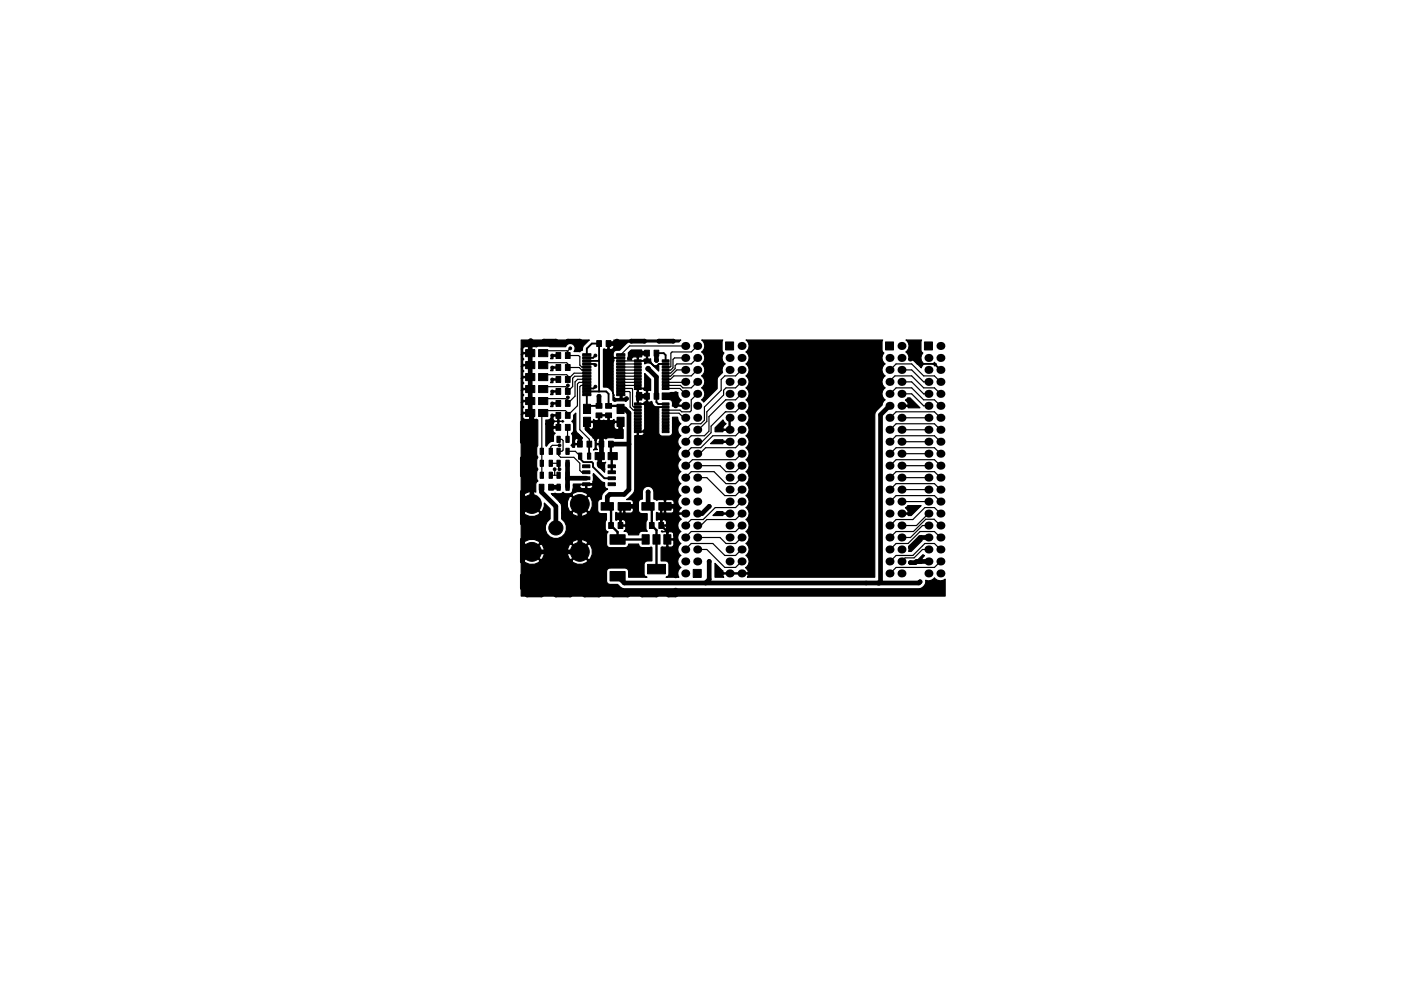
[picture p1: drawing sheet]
<svg xmlns="http://www.w3.org/2000/svg" width="297mm" height="210mm" viewBox="0 0 297 210" stroke-linecap="round" stroke-linejoin="round" font-family="sans-serif">
<g fill="#000" stroke="#000" stroke-width=".21">
<path d="M111.4 79.3h2v1.5h-2zM111.4 76.7h2v1.5h-2zM111.4 74.2h2v1.5h-2zM114.2 79.3h1.9v1.5h-1.9zM114.2 76.7h1.9v1.5h-1.9zM114.2 74.2h1.9v1.5h-1.9zM117.9 79.9h1v1.2h-1zM117.9 77.3h1v1.3h-1zM117.9 74.8h1v1.3h-1zM119.9 79.9h1v1.2h-1zM119.9 77.3h1v1.3h-1zM119.9 74.8h1v1.3h-1z"/>
<path d="M123.5 75h1.8v.5h-1.8zM123.5 75.7h1.8v.4h-1.8zM123.5 76.3h1.8v.5h-1.8zM123.5 77h1.8v.4h-1.8zM123.5 77.6h1.8v.5h-1.8zM123.5 78.3h1.8v.4h-1.8zM123.5 78.9h1.8v.5h-1.8zM123.5 79.6h1.8v.4h-1.8zM126.5 72.3h1v1.2h-1zM128.5 72.3h1v1.2h-1zM130.7 79.6h1.8v.4h-1.8zM130.7 78.9h1.8v.5h-1.8z"/>
<path d="M130.7 78.3h1.8v.4h-1.8zM130.7 77.6h1.8v.5h-1.8zM130.7 77h1.8v.4h-1.8zM130.7 76.3h1.8v.5h-1.8zM130.7 75.7h1.8v.4h-1.8zM130.7 75h1.8v.5h-1.8zM134.5 76.3h1.5v.5h-1.5zM134.5 77h1.5v.4h-1.5zM134.5 77.6h1.5v.5h-1.5zM134.5 78.3h1.5v.4h-1.5zM134.5 78.9h1.5v.5h-1.5zM136.7 74.3h1v1.2h-1z"/>
<path d="M138.7 74.3h1v1.2h-1zM140.4 78.9h1.5v.5h-1.5zM140.4 78.3h1.5v.4h-1.5zM140.4 77.6h1.5v.5h-1.5zM140.4 77h1.5v.4h-1.5zM140.4 76.3h1.5v.5h-1.5zM153.8 72.6h1.7v1.7h-1.7zM187.7 72.6h1.7v1.7h-1.7zM196 72.6h1.7v1.7h-1.7zM111.4 86.9h2v1.5h-2zM111.4 81.8h2v1.5h-2zM111.4 84.3h2v1.5h-2z"/>
<path d="M114.5 97.6h.7v1.3h-.7zM114.5 95.1h.7v1.3h-.7zM114.2 86.9h1.9v1.5h-1.9zM114.2 81.8h1.9v1.5h-1.9zM114.2 84.3h1.9v1.5h-1.9zM116.4 97.6h.7v1.3h-.7zM116.4 95.1h.7v1.3h-.7zM118.1 97.6h.7v1.3h-.7zM118.1 95.1h.7v1.3h-.7zM118.1 92.6h.7v1.3h-.7zM117.9 87.5h1v1.3h-1zM117.9 82.4h1v1.3h-1z"/>
<path d="M117.9 90h1v1.3h-1zM117.9 85h1v1.2h-1zM120 97.6h.7v1.3h-.7zM120 95.1h.7v1.3h-.7zM120 92.6h.7v1.3h-.7zM119.9 87.5h1v1.3h-1zM119.9 82.4h1v1.3h-1zM119.9 90h1v1.3h-1zM119.9 85h1v1.2h-1zM122.7 96.1h.7v1.3h-.7zM122.5 93.6h1v1.3h-1zM123.5 98.6h1.6v.6h-1.6z"/>
<path d="M123.7 85.8h1.5v1.9h-1.5zM123.7 88.5h1.5v2h-1.5zM124.6 96.1h.7v1.3h-.7zM123.5 80.2h1.8v.5h-1.8zM123.5 80.9h1.8v.4h-1.8zM123.5 81.5h1.8v.5h-1.8zM123.5 82.2h1.8v.4h-1.8zM123.5 82.8h1.8v.5h-1.8zM123.5 83.5h1.8v.4h-1.8zM124.5 93.6h1v1.3h-1zM126.4 85.6h1.2v1h-1.2zM126.4 87.6h1.2v1h-1.2z"/>
<path d="M127 93.6h1v1.3h-1zM126.2 96h1.9v1.5h-1.9zM128.4 85.6h1.3v1h-1.3zM128.4 87.6h1.3v1h-1.3zM128.9 98.6h1.6v.6h-1.6zM129 93.6h1v1.3h-1zM130.8 85.8h1.5v1.9h-1.5zM130.8 88.5h1.5v2h-1.5zM128.9 96h2v1.5h-2zM130.7 83.5h1.8v.4h-1.8zM130.7 82.8h1.8v.5h-1.8zM130.7 82.2h1.8v.4h-1.8z"/>
<path d="M130.7 81.5h1.8v.5h-1.8zM130.7 80.9h1.8v.4h-1.8zM130.7 80.2h1.8v.5h-1.8zM134.5 79.6h1.5v.4h-1.5zM134.5 80.2h1.5v.5h-1.5zM134.5 80.9h1.5v.4h-1.5zM134.5 81.5h1.5v.5h-1.5zM134.5 82.2h1.5v.4h-1.5zM134.5 85.5h1.5v.4h-1.5zM134.5 86.1h1.5v.5h-1.5zM134.5 86.8h1.5v.4h-1.5zM134.5 87.4h1.5v.5h-1.5z"/>
<path d="M134.5 88.1h1.5v.4h-1.5zM134.5 88.7h1.5v.5h-1.5zM134.5 89.4h1.5v.4h-1.5zM134.5 90h1.5v.5h-1.5zM134.5 90.7h1.5v.4h-1.5zM134.5 91.3h1.5v.5h-1.5zM136.7 83.4h1v1.3h-1zM138.7 83.4h1v1.3h-1zM140.4 82.2h1.5v.4h-1.5zM140.4 81.5h1.5v.5h-1.5zM140.4 80.9h1.5v.4h-1.5zM140.4 80.2h1.5v.5h-1.5z"/>
<path d="M140.4 79.6h1.5v.4h-1.5zM140.4 91.3h1.5v.5h-1.5zM140.4 90.7h1.5v.4h-1.5zM140.4 90h1.5v.5h-1.5zM140.4 89.4h1.5v.4h-1.5zM140.4 88.7h1.5v.5h-1.5zM140.4 88.1h1.5v.4h-1.5zM140.4 87.4h1.5v.5h-1.5zM140.4 86.8h1.5v.4h-1.5zM140.4 86.1h1.5v.5h-1.5zM140.4 85.5h1.5v.4h-1.5zM114.5 100.2h.7v1.3h-.7z"/>
<path d="M114.3 102.7h1v1.3h-1zM116.4 100.2h.7v1.3h-.7zM116.3 102.7h1v1.3h-1zM118.1 102.7h.7v1.3h-.7zM118.1 100.2h.7v1.3h-.7zM120 102.7h.7v1.3h-.7zM120 100.2h.7v1.3h-.7zM123.5 99.9h1.6v.6h-1.6zM123.5 101.2h1.6v.6h-1.6zM123.5 102.4h1.6v.6h-1.6zM128.9 102.4h1.6v.6h-1.6zM128.9 101.2h1.6v.6h-1.6z"/>
<path d="M128.9 99.9h1.6v.6h-1.6zM129.1 110.9h1v1.2h-1zM129.3 113.5h3.2v2h-3.2zM127.5 106.6h2.6v1.6h-2.6zM131.1 110.9h1v1.2h-1zM131.1 106.6h2.6v1.6h-2.6zM136.1 113.4h1.5v2h-1.5zM137.3 119.7h3.8v2h-3.8zM137.7 110.9h1v1.2h-1zM138.4 113.4h1.5v2h-1.5zM136.1 106.6h2.6v1.6h-2.6zM139.7 110.9h1v1.2h-1z"/>
<path d="M140.7 113.4h1.5v2h-1.5zM139.7 106.6h2.6v1.6h-2.6zM129.3 121.3h3.2v2h-3.2zM147 120.8h1.7v1.7h-1.7z"/>
<circle cx="112.5" cy="72.4" r=".5"/>
<circle cx="115.3" cy="72.4" r=".4"/>
<circle cx="117.1" cy="78" r=".3"/>
<circle cx="117.1" cy="75.4" r=".3"/>
<circle cx="117.9" cy="72.4" r=".4"/>
<circle cx="120.4" cy="72.4" r=".4"/>
<circle cx="120.9" cy="73.9" r=".3"/>
<circle cx="122.9" cy="72.4" r=".4"/>
<circle cx="126.2" cy="75.4" r=".3"/>
<circle cx="126.2" cy="77.5" r=".3"/>
<circle cx="130.8" cy="72.4" r=".4"/>
<circle cx="133.9" cy="74.9" r=".5"/>
<circle cx="133.9" cy="72.4" r=".4"/>
<circle cx="136.7" cy="72.4" r=".4"/>
<circle cx="137.4" cy="78.2" r=".5"/>
<circle cx="139.2" cy="76.4" r=".4"/>
<circle cx="139.7" cy="72.4" r=".4"/>
<circle cx="142.7" cy="72.4" r=".4"/>
<circle cx="193" cy="76.2" r=".4"/>
<circle cx="110.7" cy="93.7" r=".4"/>
<circle cx="110.7" cy="89.7" r=".4"/>
<circle cx="110.7" cy="97.3" r=".4"/>
<circle cx="117.1" cy="88.1" r=".3"/>
<circle cx="117.1" cy="85.6" r=".3"/>
<circle cx="117.1" cy="83.1" r=".3"/>
<circle cx="117.1" cy="90.7" r=".3"/>
<circle cx="117.1" cy="80.5" r=".3"/>
<circle cx="117.6" cy="99.6" r=".3"/>
<circle cx="118.6" cy="99.6" r=".3"/>
<circle cx="118.6" cy="94.5" r=".3"/>
<circle cx="120.4" cy="84.3" r=".3"/>
<circle cx="120.4" cy="81.8" r=".3"/>
<circle cx="122.4" cy="92.5" r=".4"/>
<circle cx="125.5" cy="91.9" r=".4"/>
<circle cx="126.2" cy="82" r=".3"/>
<circle cx="127" cy="84.1" r=".4"/>
<circle cx="127.3" cy="98.8" r=".5"/>
<circle cx="127.5" cy="91.9" r=".4"/>
<circle cx="131.6" cy="91.9" r=".4"/>
<circle cx="132.8" cy="84.6" r=".4"/>
<circle cx="135.4" cy="84.1" r=".5"/>
<circle cx="143.3" cy="93.2" r=".4"/>
<circle cx="143.3" cy="89.1" r=".4"/>
<circle cx="143.3" cy="86.1" r=".4"/>
<circle cx="143.3" cy="97.3" r=".4"/>
<circle cx="143.3" cy="83.6" r=".4"/>
<circle cx="143.3" cy="95.2" r=".4"/>
<circle cx="143.3" cy="91.2" r=".4"/>
<circle cx="143.3" cy="99.3" r=".4"/>
<circle cx="151.4" cy="82" r=".4"/>
<circle cx="110.7" cy="119.1" r=".4"/>
<circle cx="110.7" cy="114.5" r=".4"/>
<circle cx="110.7" cy="100.8" r=".4"/>
<circle cx="110.7" cy="111" r=".4"/>
<circle cx="110.7" cy="104.4" r=".4"/>
<circle cx="112.8" cy="106.9" r="2"/>
<circle cx="112.8" cy="117.1" r="2"/>
<circle cx="117.9" cy="112" r="1.5"/>
<circle cx="122.9" cy="117.1" r="2"/>
<circle cx="122.9" cy="106.9" r="2"/>
<circle cx="127.3" cy="102.9" r=".5"/>
<circle cx="134.9" cy="107.4" r=".4"/>
<circle cx="137.4" cy="104.4" r=".4"/>
<circle cx="143.3" cy="111.5" r=".4"/>
<circle cx="143.3" cy="101.3" r=".4"/>
<circle cx="143.3" cy="109.5" r=".4"/>
<circle cx="143.3" cy="105.4" r=".4"/>
<circle cx="143.3" cy="118.1" r=".4"/>
<circle cx="143.3" cy="103.4" r=".4"/>
<circle cx="143.3" cy="107.4" r=".4"/>
<circle cx="143.3" cy="116.1" r=".4"/>
<circle cx="143.3" cy="113.5" r=".4"/>
<circle cx="150.4" cy="107.4" r=".4"/>
<circle cx="150.4" cy="119.1" r=".4"/>
<circle cx="193" cy="119.4" r=".4"/>
<circle cx="193" cy="116.1" r=".4"/>
<circle cx="110.7" cy="122.2" r=".4"/>
<circle cx="110.7" cy="124.7" r=".4"/>
<circle cx="111.8" cy="126.2" r=".4"/>
<circle cx="114.8" cy="126.2" r=".4"/>
<circle cx="117.9" cy="126.2" r=".4"/>
<circle cx="120.9" cy="126.2" r=".4"/>
<circle cx="124" cy="126.2" r=".4"/>
<circle cx="127" cy="126.2" r=".4"/>
<circle cx="130" cy="126.2" r=".4"/>
<circle cx="133.1" cy="126.2" r=".4"/>
<circle cx="136.1" cy="126.2" r=".4"/>
<circle cx="139.2" cy="126.2" r=".4"/>
<circle cx="141.7" cy="126.2" r=".4"/>
<circle cx="143.3" cy="122.2" r=".4"/>
<circle cx="143.3" cy="125.2" r=".4"/>
<circle cx="143.3" cy="120.1" r=".4"/>
<circle cx="195.1" cy="123.4" r=".4"/>
</g>
<g fill="#000">
<circle cx="145.3" cy="78.5" r=".85"/>
<circle cx="145.3" cy="75.9" r=".85"/>
<circle cx="145.3" cy="73.4" r=".85"/>
<circle cx="147.8" cy="78.5" r=".85"/>
<circle cx="147.8" cy="73.4" r=".85"/>
<circle cx="147.8" cy="75.9" r=".85"/>
<circle cx="154.7" cy="78.5" r=".85"/>
<circle cx="154.7" cy="75.9" r=".85"/>
<circle cx="157.2" cy="78.5" r=".85"/>
<circle cx="157.2" cy="73.4" r=".85"/>
<circle cx="157.2" cy="75.9" r=".85"/>
<circle cx="188.6" cy="78.5" r=".85"/>
<circle cx="188.6" cy="75.9" r=".85"/>
<circle cx="191.1" cy="78.5" r=".85"/>
<circle cx="191.1" cy="73.4" r=".85"/>
<circle cx="191.1" cy="75.9" r=".85"/>
<circle cx="196.8" cy="78.5" r=".85"/>
<circle cx="196.8" cy="75.9" r=".85"/>
<circle cx="199.4" cy="73.4" r=".85"/>
<circle cx="199.4" cy="78.5" r=".85"/>
<circle cx="199.4" cy="75.9" r=".85"/>
<circle cx="145.3" cy="96.3" r=".85"/>
<circle cx="145.3" cy="88.6" r=".85"/>
<circle cx="145.3" cy="83.6" r=".85"/>
<circle cx="145.3" cy="81" r=".85"/>
<circle cx="145.3" cy="93.7" r=".85"/>
<circle cx="145.3" cy="86.1" r=".85"/>
<circle cx="145.3" cy="98.8" r=".85"/>
<circle cx="145.3" cy="91.2" r=".85"/>
<circle cx="147.8" cy="93.7" r=".85"/>
<circle cx="147.8" cy="88.6" r=".85"/>
<circle cx="147.8" cy="86.1" r=".85"/>
<circle cx="147.8" cy="96.3" r=".85"/>
<circle cx="147.8" cy="91.2" r=".85"/>
<circle cx="147.8" cy="81" r=".85"/>
<circle cx="147.8" cy="98.8" r=".85"/>
<circle cx="147.8" cy="83.6" r=".85"/>
<circle cx="154.7" cy="93.7" r=".85"/>
<circle cx="154.7" cy="96.3" r=".85"/>
<circle cx="154.7" cy="81" r=".85"/>
<circle cx="154.7" cy="86.1" r=".85"/>
<circle cx="154.7" cy="83.6" r=".85"/>
<circle cx="154.7" cy="91.2" r=".85"/>
<circle cx="154.7" cy="98.8" r=".85"/>
<circle cx="154.7" cy="88.6" r=".85"/>
<circle cx="157.2" cy="96.3" r=".85"/>
<circle cx="157.2" cy="93.7" r=".85"/>
<circle cx="157.2" cy="86.1" r=".85"/>
<circle cx="157.2" cy="81" r=".85"/>
<circle cx="157.2" cy="83.6" r=".85"/>
<circle cx="157.2" cy="88.6" r=".85"/>
<circle cx="157.2" cy="91.2" r=".85"/>
<circle cx="157.2" cy="98.8" r=".85"/>
<circle cx="188.6" cy="96.3" r=".85"/>
<circle cx="188.6" cy="88.6" r=".85"/>
<circle cx="188.6" cy="86.1" r=".85"/>
<circle cx="188.6" cy="93.7" r=".85"/>
<circle cx="188.6" cy="83.6" r=".85"/>
<circle cx="188.6" cy="91.2" r=".85"/>
<circle cx="188.6" cy="81" r=".85"/>
<circle cx="188.6" cy="98.8" r=".85"/>
<circle cx="191.1" cy="86.1" r=".85"/>
<circle cx="191.1" cy="83.6" r=".85"/>
<circle cx="191.1" cy="88.6" r=".85"/>
<circle cx="191.1" cy="91.2" r=".85"/>
<circle cx="191.1" cy="93.7" r=".85"/>
<circle cx="191.1" cy="96.3" r=".85"/>
<circle cx="191.1" cy="81" r=".85"/>
<circle cx="191.1" cy="98.8" r=".85"/>
<circle cx="196.8" cy="91.2" r=".85"/>
<circle cx="196.8" cy="86.1" r=".85"/>
<circle cx="196.8" cy="88.6" r=".85"/>
<circle cx="196.8" cy="93.7" r=".85"/>
<circle cx="196.8" cy="81" r=".85"/>
<circle cx="196.8" cy="83.6" r=".85"/>
<circle cx="196.8" cy="96.3" r=".85"/>
<circle cx="196.8" cy="98.8" r=".85"/>
<circle cx="199.4" cy="88.6" r=".85"/>
<circle cx="199.4" cy="83.6" r=".85"/>
<circle cx="199.4" cy="86.1" r=".85"/>
<circle cx="199.4" cy="91.2" r=".85"/>
<circle cx="199.4" cy="93.7" r=".85"/>
<circle cx="199.4" cy="96.3" r=".85"/>
<circle cx="199.4" cy="81" r=".85"/>
<circle cx="199.4" cy="98.8" r=".85"/>
<circle cx="145.3" cy="114" r=".85"/>
<circle cx="145.3" cy="119.1" r=".85"/>
<circle cx="145.3" cy="116.6" r=".85"/>
<circle cx="145.3" cy="109" r=".85"/>
<circle cx="145.3" cy="101.3" r=".85"/>
<circle cx="145.3" cy="111.5" r=".85"/>
<circle cx="145.3" cy="103.9" r=".85"/>
<circle cx="145.3" cy="106.4" r=".85"/>
<circle cx="147.8" cy="109" r=".85"/>
<circle cx="147.8" cy="116.6" r=".85"/>
<circle cx="147.8" cy="103.9" r=".85"/>
<circle cx="147.8" cy="119.1" r=".85"/>
<circle cx="147.8" cy="114" r=".85"/>
<circle cx="147.8" cy="111.5" r=".85"/>
<circle cx="147.8" cy="101.3" r=".85"/>
<circle cx="147.8" cy="106.4" r=".85"/>
<circle cx="154.7" cy="103.9" r=".85"/>
<circle cx="154.7" cy="109" r=".85"/>
<circle cx="154.7" cy="116.6" r=".85"/>
<circle cx="154.7" cy="119.1" r=".85"/>
<circle cx="154.7" cy="111.5" r=".85"/>
<circle cx="154.7" cy="114" r=".85"/>
<circle cx="154.7" cy="101.3" r=".85"/>
<circle cx="154.7" cy="106.4" r=".85"/>
<circle cx="157.2" cy="114" r=".85"/>
<circle cx="157.2" cy="119.1" r=".85"/>
<circle cx="157.2" cy="106.4" r=".85"/>
<circle cx="157.2" cy="111.5" r=".85"/>
<circle cx="157.2" cy="116.6" r=".85"/>
<circle cx="157.2" cy="101.3" r=".85"/>
<circle cx="157.2" cy="109" r=".85"/>
<circle cx="157.2" cy="103.9" r=".85"/>
<circle cx="188.6" cy="109" r=".85"/>
<circle cx="188.6" cy="116.6" r=".85"/>
<circle cx="188.6" cy="101.3" r=".85"/>
<circle cx="188.6" cy="103.9" r=".85"/>
<circle cx="188.6" cy="106.4" r=".85"/>
<circle cx="188.6" cy="111.5" r=".85"/>
<circle cx="188.6" cy="119.1" r=".85"/>
<circle cx="188.6" cy="114" r=".85"/>
<circle cx="191.1" cy="111.5" r=".85"/>
<circle cx="191.1" cy="109" r=".85"/>
<circle cx="191.1" cy="116.6" r=".85"/>
<circle cx="191.1" cy="101.3" r=".85"/>
<circle cx="191.1" cy="103.9" r=".85"/>
<circle cx="191.1" cy="106.4" r=".85"/>
<circle cx="191.1" cy="119.1" r=".85"/>
<circle cx="191.1" cy="114" r=".85"/>
<circle cx="196.8" cy="101.3" r=".85"/>
<circle cx="196.8" cy="109" r=".85"/>
<circle cx="196.8" cy="116.6" r=".85"/>
<circle cx="196.8" cy="103.9" r=".85"/>
<circle cx="196.8" cy="106.4" r=".85"/>
<circle cx="196.8" cy="111.5" r=".85"/>
<circle cx="196.8" cy="119.1" r=".85"/>
<circle cx="196.8" cy="114" r=".85"/>
<circle cx="199.4" cy="116.6" r=".85"/>
<circle cx="199.4" cy="101.3" r=".85"/>
<circle cx="199.4" cy="103.9" r=".85"/>
<circle cx="199.4" cy="106.4" r=".85"/>
<circle cx="199.4" cy="109" r=".85"/>
<circle cx="199.4" cy="114" r=".85"/>
<circle cx="199.4" cy="111.5" r=".85"/>
<circle cx="199.4" cy="119.1" r=".85"/>
<circle cx="145.3" cy="121.7" r=".85"/>
<circle cx="154.7" cy="121.7" r=".85"/>
<circle cx="157.2" cy="121.7" r=".85"/>
<circle cx="188.6" cy="121.7" r=".85"/>
<circle cx="191.1" cy="121.7" r=".85"/>
<circle cx="196.8" cy="121.7" r=".85"/>
<circle cx="199.4" cy="121.7" r=".85"/>
</g>
<g fill="none" stroke="#000" stroke-width=".25">
<path d="M115.2 77.5l.5-.5h4.4l.3 .2v.8h2.4l.6 .5h1M117.1 78h1.3M120.4 74.7l-.3-.3h-4.4l-.5 .5M120.9 73.9l-.5 .5v1h2.3l.2 .3v1.8l.4 .4h1.1M124.4 79.2h-2.7l-1.3 1.3v-.8l-.3-.2h-4.4l-.5 .5M124.4 79.8h-2.6l-.4 .5v1.7l-1 1.1v-1.3M131.6 79.2h3.6M131.6 76.6h3.6M131.6 78.5h3.6M131.6 79.8h3.6M131.6 77.9h3.6M131.6 77.2h3.6"/>
<path d="M145.3 75.9h-2.3l-.3 .4v1.7l-.5 .5h-1.1M145.3 78.5h-1.8l-1.3 1.3h-1.1M145.3 73.4h-11.8l-1.9 1.9M147.8 75.9l-1.2 1.3h-3.1l-.4 .4v.6l-.9 1h-1.1M147.8 73.4l-1.2 1.3h-4.1l-.3 .2v2.8l-.1 .2h-1M147.8 78.5l-1.2 1.3h-3.7l-.7 .7h-1.1M157.2 78.5l-1.2 1.3h-2.3l-.8 .7v2.3l-3.5 3.6v2.7l-.8 .8h-2l-1.3 1.3M188.6 78.5l1.4-1.3h3.3l2.5 2.6h2.3l1.3 1.2M191.1 78.5h2.2l2.5 2.5h1M116.8 98.3h1.6v1.1l.2 .2M117.1 88.1h1.3M117.1 85.6h1.3"/>
<path d="M117.1 83.1h1.3M117.1 80.5h1.3M117.6 99.6v1.2M118.4 93.2h.7l.3 .3v2l-.3 .3h-.7v.8l.5 .4h2.8l1.2 1.3v1.5l.4 .4h1M118.6 94.5h-1.5l-.3 .3v1M120.3 95.8h1.7l1 1v.3M120.4 82.5l-.5-.5h-4.2l-.5 .5M120.4 90.7l-.1 2.5M120.4 85.1l-.5-.5h-4.2l-.5 .5M120.4 81.8h.1M120.4 84.3h.1M124.4 80.5h-1.9l-.6 .5v3.1l-1.5 1.5v-1.3"/>
<path d="M124.4 81.1h-1.6l-.4 .4v4.6l-2 2v-.5l-.5-.5h-4.2l-.8 .8v12.9M124.4 81.8h-1.2l-.3 .2v9.2l2.1 2v1M125 96.7l-.1 .1M125.1 86.1l-.7 .6M131.6 83.1h1.8l.2 .1v3.2l.7 .6h.9M131.6 81.1h3.6M131.6 81.8h3.6M131.6 82.4h2.4l.1 .1v3.6l.3 .3h.8M131.6 80.5h3.6M141.1 87.7h2.9l1 .9h.3M141.1 82.4h3l1.2 1.2M145.3 81l-4.2 .1"/>
<path d="M147.8 81l-1.2 1.3h-1.8l-.5-.5h-3.2M147.8 98.8h4.9l1.2 1.3h2.1l1.2-1.3M147.8 83.6l-1.2 1.2v2.3l-.3 .3h-1.8l-.3-.4h-3.1M157.2 96.3l-1.2 1.2h-9.2l-1.3 1.3h-.2M157.2 93.7l-1.2 1.3h-6.4l-1.3 1.3h-.5M157.2 86.1l-1.2 1.3h-2.2l-3 3v1.4l-2 1.9h-1M157.2 91.2l-1.2 1.3h-4.9l-2.5 2.5h-2l-1.3 1.3M157.2 81l-1.2 1.3h-2.1l-.5 .5v1l-3.5 3.6v2l-1.8 1.8h-.3M157.2 83.6l-1.2 1.2h-2.1l-3.6 3.6v3.1l-.9 1h-2.8l-1.3 1.2M188.6 81l1.1-1.2h3.6l2.5 2.5h2.3l1.3 1.3M188.6 98.8l1.4-1.3h8.1l1.3 1.3M188.6 96.3l1.4-1.3h8.1l1.3 1.3"/>
<path d="M188.6 93.7l1.4-1.2h8.1l1.3 1.2M188.6 91.2l1.4-1.3h8.1l1.3 1.3M188.6 88.6l1.4-1.2h8.1l1.3 1.2M188.6 83.6l1.4-1.3h3.3l2.5 2.5h2.3l1.3 1.3M191.1 98.8h5.7M191.1 96.3h5.7M191.1 93.7h5.7M191.1 91.2h5.7M191.1 88.6h5.7M191.1 83.6h2.2l2.5 2.5h1M191.1 81h2.2l2.5 2.6h1M116.8 100.8h1.6"/>
<path d="M145.3 116.6l1.3-1.3h4.5l2.6 2.6h2.3l1.2-1.3M145.3 101.3l1.3-1.2h4.8l2.5 2.5h2.1l1.2-1.3M147.8 116.6h2.1l3.8 3.8h2.3l1.2-1.3M147.8 114h4.9l1.2 1.3h2.1l1.2-1.3M147.8 101.3h2.1l3.8 3.9h2.3l1.2-1.3M157.2 109l-1.2 1.2h-6.1l-1.3 1.3h-.8M157.2 111.5l-1.2 1.3h-9.4l-1.3 1.2M157.2 106.4l-1.2 1.3h-4.4l-2.5 2.5h-2.5l-1.3 1.3M188.6 106.4l1.4-1.2h8.1l1.3 1.2M188.6 103.9l1.4-1.3h8.1l1.3 1.3M188.6 101.3l1.4-1.2h8.1l1.3 1.2M191.1 106.4h5.7"/>
<path d="M191.1 103.9h5.7M191.1 101.3h5.7M196.8 116.6h-1.2l-1.8 1.8h-1.9l-.8 .7M196.8 111.5h-1.2l-2.6 2.5h-1.9M196.8 109l-2.5 2.5h-3.2M199.4 119.1l-1.3 1.3h-8.1l-1.4 1.3M199.4 114l-1.3-1.2h-3l-2.6 2.5h-2.5l-1.3 1.3-.1-.1M199.4 116.6l-1.3-1.3h-2l-2.6 2.6h-3.5l-1.4 1.2M199.4 111.5l-1.3-1.3h-1.8l-2.6 2.6h-3.7l-1.4 1.2M199.4 109l-1.3-1.3h-2l-2.6 2.5h-3.5l-1.4 1.3"/>
</g>
<g fill="none" stroke="#000" stroke-width="1">
<path d="M112.5 72.4l-.1 15.2 .4 .4v18.9M115.3 72.4h2.6M120.4 72.4h2.5M130.8 72.4l-.5 .5h-1.3M133.9 72.4h2.8M133.9 74.9h3.3M137.4 78.2l1.8 1.8v4.1M139.2 74.9v1.5M139.2 76.4h.1M139.7 72.4h3M110.7 89.7v4M110.7 97.3v3.5"/>
<path d="M120.3 98.3v5.1M122.4 92.5l.6 .5v1.2M124.5 89.5v1.4l1 1M127 84.1v2M127.1 96.8l.2 2M127.5 91.9v.1M127.5 92v4.4M129.5 94.2h3.8M131.6 89.5v2.4M131.6 86.8h.9l.8 .8v16.3l-1 1h-3l-.5 .5v2M135.4 84.1h1.8M143.3 83.6v2.5"/>
<path d="M143.3 91.2v2M143.3 95.2v2.1M143.3 99.3v2M188.6 86.1l-1.9 1.9v35.4l-.3 .3M110.7 104.4v6.6M110.7 114.5v4.6M114.8 103.4v1l3.1 3v4.6M116.8 103.4h1.6M122.9 106.9v10.2h-10.1M124.3 101.5h-4v.1M132.4 107.4h2.5M137.4 104.4v3"/>
<path d="M137.4 107.4h.1M141 107.4h2.3v2.1M143.3 103.4v2M143.3 111.5v2M143.3 116.1v2M150.4 107.4l-1.6 1.6h-1M150.4 119.1v3.8l-.8 .8M196.8 114h-1.7l-2.1 2.1M196.8 119.1h-2.5l-.2 .3h-1.1M110.7 122.2v2.5M111.8 126.2h3M117.9 126.2h3"/>
<path d="M124 126.2h3M130 126.2h3.1M130.9 122.3l1.5 1.4h62.4l.3-.3M136.1 126.2h3.1M143.3 120.1v2.1M143.3 125.2v1h-1.6"/>
</g>
<g fill="none" stroke="#000" stroke-width=".4">
<path d="M124.4 77.2h1.6l.2 .3M124.4 75.3v-1.3l1.1-1.1h1.5v10.2M126.2 75.4l-.5 .5h-1.3M127 76.6h-2.6M127 76.4h.1M129 72.9v2l1 1h1.6M137.2 76.2l1.5 1.5h.5l.5-.5h1.4M137.2 74.9v1.3M137.2 76.2l-.4 .4h-1.6M139.2 74.9h1.5l.4 .4v1.3M193 76.2h.5l1.1 1h3.5l1.3 1.3M123 96.8v.5l.7 .7h1.8l.2 .3v.8l2.4 2.4h1.6"/>
<path d="M124.4 83.1h4.1l.5 .5v2.5M124.5 89.5h7.1M124.6 83.7h-.2l.1 3.1 .6-.7h1.9M125 94.2l-.1 2.6M126.2 82l-.3 .4h-1.5M127 88.1v1.4h.3M129 88.1v1.6M131.6 83.7l.2 .2v.7h1M135.2 82.4h1.6l.4 .4v7.9l-.9 .9h-1.1M137.2 86.4h3.9M137.2 86.4h.1M137.2 85.1l-.7 .6h-1.3"/>
<path d="M139.2 84.1v1.2l.4 .4h1.5"/>
</g>
<path d="M117.1 75.4h1.3M117.1 90.7h1.3M127.5 96.4l-.4 .4M129 86.1h1.9l.7 .7M129.5 94.2v2.2l.4 .4-.2 .2v3.2M124.3 102.7h2.8l.2 .2M128.8 107.4l.8 .8v3.3l1.3 1.4v1.6l6-.1M132.4 107.4l-.8 .8v3.3M137.4 107.4l.8 .8v3.3l1 1v8.2M141 107.4l-.8 .8v3.3l1.3 1.3v1.6" fill="none" stroke="#000" stroke-width=".5"/>
<g fill="#000" stroke="#000" stroke-width=".25">
<path d="M116.9 77.8h1.6v.3h-1.1l-.2 .2v.3h-.5zM116.9 75.3h1.6v.3h-1.1l-.2 .1v.4h-.5zM110.5 72.1h14.5l-1.2 1.2-.2 .3-.1 .7-.6 .3h-1.2l.1-.1a1.04 1.04 0 0 0-.4-1.5 1.04 1.04 0 0 0-1.5 .6l-5.7-.2-.5 .2-1-.1-.2 .2v15.2l.2 .1 1-.1 .3 .2v5.5a2.52 2.52 0 0 0-.2 2.1l.2 .4a2.52 2.52 0 0 0-.2 2.1l.2 .5a2.52 2.52 0 0 0-.2 2.1l.3 .3-.3 .1-.2 .5v1.7a2.09 2.09 0 0 0-2.5 .7l3.6 3.5 .3-.2 .4-1v-.7l1.2 1.2v2.2a2.27 2.27 0 0 0-.5 3.4 2.27 2.27 0 0 0 3.5 0 2.27 2.27 0 0 0-.5-3.4v-1.3h2.1a2.16 2.16 0 0 0 3.4 0l-1.7-1.7-1.7 1.7h-2.1l-.1-1.8-.4-.6h1.7v1.1l.4 .9 .4 .2 1.7-1.7h.3l1.7 1.7 .4-.2a2.29 2.29 0 0 0-.4-3.2l-1.7 1.7h-.3l-1.7-1.7-.4 .3-.4 .9h-1.7l-1.4-1.3h4l1.7 1.6 1.7-1.6a2.16 2.16 0 0 0-3.4 0h-4l-.3-.4h.9a1.51 1.51 0 0 0 1.6-.3 1.21 1.21 0 0 0 2-.4l.2-1h1.3l.3 .6 .8 .1 .2-.2v-.6h.2v.6l.2 .2 .8-.1 .3-.4-.1-.3-4 .1v-.3l4-.1 .2-.8v-1.3l1.7 1.6 .7 .3a1.04 1.04 0 0 0 .4 1.3l.2 .1-.4 .2a1.8 1.8 0 0 0-.9 1.9h-.3l-.4 .4-.1 1.9a.74 .74 0 0 0 .8 .8h1.1v1.3l-.2 .3a2.5 2.5 0 0 0 .1 2l.4 .2-.3 .7v2a.74 .74 0 0 0 .7 .7h3.2l.6-.2 .2-.6h2.1a.74 .74 0 0 0 .7 .8l2.1-.1v2.9l-1.2 .1-.4 .4v2.2a.71 .71 0 0 0 .6 .8h-3.9v-1.2a.74 .74 0 0 0-.8-.8h-3.2l-.5 .2-.2 .6v2a.74 .74 0 0 0 .7 .7h1.6l1 .8 .5 .1 62.9-.1a1.61 1.61 0 0 0 .9-1.7 1.6 1.6 0 0 0 1.9-.5 1.56 1.56 0 0 0 2.3 .3v3.6h-89.9v-7.5h.6a2.16 2.16 0 0 0 3.4 0h6.7l.3 .3a2.29 2.29 0 0 0 3.1-.3l-1.7-1.7-1.7 1.7h-6.7l-1.7-1.7-1.7 1.7h-.6v-.5l.4 .3 1.7-1.7h.4l1.7 1.7 .3-.2 .4-1v-1h4.9v1l.4 1 .4 .2 1.7-1.7h.3l1.7 1.7a2.16 2.16 0 0 0 0-3.4l-1.7 1.7h-.3l-1.7-1.7-.4 .2-.4 1h-4.9l-.4-1-.3-.2-1.7 1.7h-.4l-1.7-1.7-.4 .3v-.5h.6l1.7 1.7 1.7-1.7h6.7l1.7 1.7 1.7-1.7-.2-.4a2.29 2.29 0 0 0-3.2 .4h-6.7l-.2-.4a2.29 2.29 0 0 0-3.2 .4h-.6v-6.4h.6l.2 .4a2.29 2.29 0 0 0 3.2-.4l-1.7-1.7-1.7 1.7h-.6v-.5l.4 .3 1.7-1.7-1.7-1.7-.4 .3v-17.6h.3v.6l.3 .4 1 .1 .2-.1v-1.1h-1.3l-.5 .1v-2.5h.3v.6l.3 .4-.3 .3v.6l.2 .2h1.3v-2.3h-1.3l-.5 .2v-2.6h.3v.6l.3 .4-.3 .4v.6l.2 .2h1.3v-2.3h-1.3l-.5 .1v-2.5h.3v.6l.3 .4-.3 .4v.6l.2 .1h1.3v-2.3h-1.3l-.5 .2v-2.5h.3v.5l.3 .4-.3 .4v.6l.2 .2h1.3v-2.3h-1.3l-.5 .2v-2.6h.3v.6l.3 .4-.3 .4v.6l.2 .1h1.3v-2.2h-1.3l-.5 .1v-1.2h.3v.6l.2 .2h1.3v-1.1l-.2-.2h-.8l-.5 .5h-.3zM133.8 74.3h2.2v.3l.2 .2h1.1v1.2l.2 .2 .4-.1a1.28 1.28 0 0 0 1.8 1.5v1.1l-1.6-1.5a1.35 1.35 0 0 0-1.4 0l-.3-.8 .2-.2 .4-.2v-.9h-.8l-.2 .1 .1 .5h-.6l-.1 .2v.4h-.3v-.4l-.2-.2h-.5l-.4 .3-.1 .4h-.8l-.1-.4 .2-.2a1.54 1.54 0 0 1 .6-1.5zM136.7 79.2l1.2 1.3v2.4l-.4-.1-.2 .2v2.2a.55 .55 0 0 0 .8 0 2.01 2.01 0 0 0 1.6 1.4v4.7a.89 .89 0 0 0 .7 1.2h1.7a1.26 1.26 0 0 0 .5-1.4v-2.6h1l.2 .7 .6 .7-.3 .2a1.54 1.54 0 0 0 .3 2.4 1.51 1.51 0 0 0 0 2.5 1.51 1.51 0 0 0 0 2.5 1.51 1.51 0 0 0 0 2.6 1.51 1.51 0 0 0 0 2.5 1.51 1.51 0 0 0 0 2.6 1.51 1.51 0 0 0 .1 2.5l-.5 .5-.2 .4 .2 .2h1.4v.3h-1.4l-.2 .2 .2 .4 .5 .5-.4 .2a1.54 1.54 0 0 0 .3 2.4 1.51 1.51 0 0 0 0 2.5 1.51 1.51 0 0 0 0 2.6 1.51 1.51 0 0 0 0 2.5 1.47 1.47 0 0 0-.5 2.1h-2.7l.6-.5v-2.3a.74 .74 0 0 0-.7-.7h-.9v-2.9l.2-.1 .8 .1 .2-.2v-1.3h.2v1.3l.2 .2h.6l.4-.3 .1-1.1-.2-.1h-1.4l.1-1.6h.2v1.3h1.1l.2-.1v-.9l-.5-.5-1 .2-.2-.2-.8 .1-.2-.1 .1-.2 .2 .2a.68 .68 0 0 0 .8-.5v-.5l-.1-.2h-1.2l.1-1.2h.2v1h.9l.1-.2-.1-.7a.59 .59 0 0 0-.9-.1l-.4-.2-.7 .1 .1-1.6 .3 .2h1.1l.2-.2v-1.1h.2v1.1l.2 .2h1.1l.5-.5v-.7l-.1-.1h-2l.1-1.4h.2v1.1h1.7l.1-.1-.1-.9-.4-.3h-1.1l-.2 .2a2.11 2.11 0 0 0-1.8-.1l-.7-.2v-1.5a1.23 1.23 0 0 0-1.2-1.2 1.23 1.23 0 0 0-1.2 1.2l-.1 1.5a.74 .74 0 0 0-.7 .7v1.9l.4 .4 1.4 .1v1.3a2.45 2.45 0 0 0-.2 2.1l.3 .3-1.4 .1-.4 .4-.1 .3h-2.1a.79 .79 0 0 0-1-.8l.3-.2 .1-.7-.2-.2h-1.1v-1.2h.3v1h.8l.2-.2v-.5a.61 .61 0 0 0-1-.3l-.4-.2-.8 .1 .1-1.6 .3 .2h1.2l.1-.2v-1.1h.3v1.1l.1 .2h1.2l.5-.5v-.7l-.2-.1h-1.9v-.3h1.9l.2-.1-.1-.9-.4-.3h-1l.4-.2a2.98 2.98 0 0 0 1.4-1.9v-11.5l.5-.1v-.4h.3v.4l.1 .1 .8-.1 .3-.4-.2-.2 .3-.6v-5l-.3-.5 .2-.3 .4-.1v-1h-.8l-.2 .2 .1 .5h-.6l-.1 .1v.4h-.3l-.1-2.1 .1-.6h.3v.4l.1 .2h.6l-.1 .5 .2 .1h.8v-.9l-.4-.2-.2-.3 .3-.5zM128.9 72.8h1.1l.2-.2v-.5h14.2l-.4 .4h-10.5l-.6 .3-1.5 1.5h-.7a1 1 0 0 0-.5 1.7l-.2 1v6.3l.3 .5-.2 .3 .3 .4 .9 .1 .2-.2v-.4h.2v.4l.2 .2 .9-.1v.7l-.5-.2-2.1 .1-.2-.2-.1-1.7-.7-.8a1.29 1.29 0 0 0-1.3-.3v-8l.2-.1a.55 .55 0 0 0 .8 0v-1h.2v1a.6 .6 0 0 0 1.1-.4v-.4l-.2-.2h-1.1zM148.8 72.1h4.4l-.1 .5v1.7l.4 .6a1.51 1.51 0 0 0 .3 2.3 1.49 1.49 0 0 0-.6 1.9 2.27 2.27 0 0 0-1.1 1.4v1.9l-2.9 2.9-.5-.5a1.51 1.51 0 0 0 0-2.5 1.51 1.51 0 0 0 0-2.5 1.51 1.51 0 0 0 0-2.6 1.51 1.51 0 0 0 0-2.5 1.51 1.51 0 0 0 .1-2.6zM158.2 72.1h28.9l-.1 .5v1.7l.4 .6a1.51 1.51 0 0 0 .3 2.3 1.51 1.51 0 0 0 0 2.6 1.51 1.51 0 0 0 0 2.5 1.51 1.51 0 0 0 0 2.5l-.6 .7-.1 .4-1.2 1.2-.3 .9v34.5h-27l.2-.5-.2-.2h-5.1l-.2 .2 .2 .5h-1.8v-3l1.7 1.7 .1 .3h5.1l.2-.2-.2-.4-.4-.5a1.51 1.51 0 0 0 0-2.5 1.51 1.51 0 0 0 0-2.6 1.51 1.51 0 0 0 0-2.5 1.51 1.51 0 0 0 0-2.6 1.51 1.51 0 0 0 0-2.5 1.51 1.51 0 0 0 0-2.5 1.51 1.51 0 0 0 0-2.6 1.51 1.51 0 0 0 0-2.5 1.51 1.51 0 0 0 0-2.6 1.51 1.51 0 0 0 0-2.5 1.51 1.51 0 0 0 0-2.5 1.51 1.51 0 0 0 0-2.6 1.51 1.51 0 0 0 0-2.5 1.51 1.51 0 0 0 0-2.6 1.51 1.51 0 0 0 0-2.5 1.51 1.51 0 0 0 0-2.5 1.51 1.51 0 0 0 0-2.6 1.51 1.51 0 0 0 0-2.5 1.51 1.51 0 0 0 .1-2.6zM192.1 72.1h3.3l-.1 .5v1.7l.4 .6a1.51 1.51 0 0 0 .2 2.3l-.6 .8-1.7-1.6h-.9a1.44 1.44 0 0 0-.7-1.7 1.51 1.51 0 0 0 .1-2.6zM197.8 77.2l.3-.3 .5 .4-.4 .3zM199.3 78.3l.2 .1v.2h-.3zM115.7 89.1a.87 .87 0 0 0 1.2-.7h.3v.5a.61 .61 0 0 0 1.1 .3v-.9l-1.4 .1v-.4h1.6v1.2a.55 .55 0 0 0 .8 0l.2 .2-.2 .2a.55 .55 0 0 0-.8 0v1.2h-1.1l-.2 .2 .1 .7 .4 .2-.3 .4-.1 1.3a1.92 1.92 0 0 0-1.5 1.1l-.1-4.8h1.5v.5l.2 .1h.9v-.9a.6 .6 0 0 0-1.1 .3h-1.5z"/>
<path d="M116.9 85.4h1.6v.3h-1.1l-.2 .2v.4h-.5zM116.9 82.9h1.6v.3h-1.1l-.2 .1v.4h-.5zM116.9 80.3l1.6 .1v.2h-1.1l-.2 .2v.4h-.5zM121.6 88.1l.5-.5v3.9l1.4 1.5-.4 .1v1.3h-1.1l-.2 .1v.4h-.4l-.3-.4a.88 .88 0 0 0 .3-1h.4v.4l.2 .2h.8v-1a.6 .6 0 0 0-1 .4h-.4v-.9l-.2-.6 .2-.2a2.45 2.45 0 0 0 .2-2l-.4-.4 .4-.4zM124.3 89.4h1.4l.1-.4 .4 .3h.5l.2-.2v-.9h.2v.9l.2 .2 .7-.2 .7 .2 .2-.2v-.9h-2v-.2h2.3v1.1l.1 .2h.5l.4-.3 .1 .4h1.4v1.6l.4 .1v1.9l-1.8-.1a2.17 2.17 0 0 0-1.8 .2 .55 .55 0 0 0-.8 0v1.3h-1.2l-.1 .1v.5l.3 .4-.9 .1 .4-.6v-1.4h.2v.4l.1 .2h.9v-1a.6 .6 0 0 0-1 .4h-.2l-.6-.9-1.5-1.5 .2-.1v-1.4h.3v1.4l.1 .1h.6l.4-.3 .1-1h4.4l.1 1 .4 .3h.6l.1-.1v-1.4h-1.1l-.1 .2h-4.4l-.1-.2h-1.4zM127 96.6h.3v1.4l.1 .2 1-.1a1.46 1.46 0 0 0-.1 1.5l-.1 .6-1.5-1.5-.1-.5 .4-.2zM140.4 83.4l3.3-.1a1.43 1.43 0 0 0 .8 1.6l-.5 .4-.2 .4 .2 .3h1.4v.2h-2.9l.1-.3a.9 .9 0 0 0-.7-1.2h-1.5zM151.5 93.3h1.8l.1 .3h1.4v.2h-1.4l-.1 .3h-2.7zM153.3 89.1l.7 .8-.6 .5-.2 .4 .2 .3h1.2l-.1-2.6h.3v2.8h-1.4l-.1 .3h-1.7v-.8zM192 84.9l.5-.5h.4l2.1 2.1h-2.4l-.1-.3h-1.5v-.2h1.5l.1-.3-.2-.4zM152 108.5h1.3l.1 .3h1.4v.3h-1.4l-.1 .3h-2.1zM192 107.7l.5-.4h2.8l-2.1 2.1h-.6l-.1-.3h-1.5v-.3h1.5l.1-.2-.2-.4z"/>
<path d="M192.7 116.1l.4-.2 2.3-2.3 .1 .3h1.5v.3h-1.5l-.1 .2 .1 .3-2.3 2.3h-.5zM192.7 119.2l1.4-.1 1.6-1.4 .3 .2-.4 .5-.2 .4 .1 .2h1.5v.3l-1.5-.1-.1 .3h-2.7z"/>
</g>
</svg>
